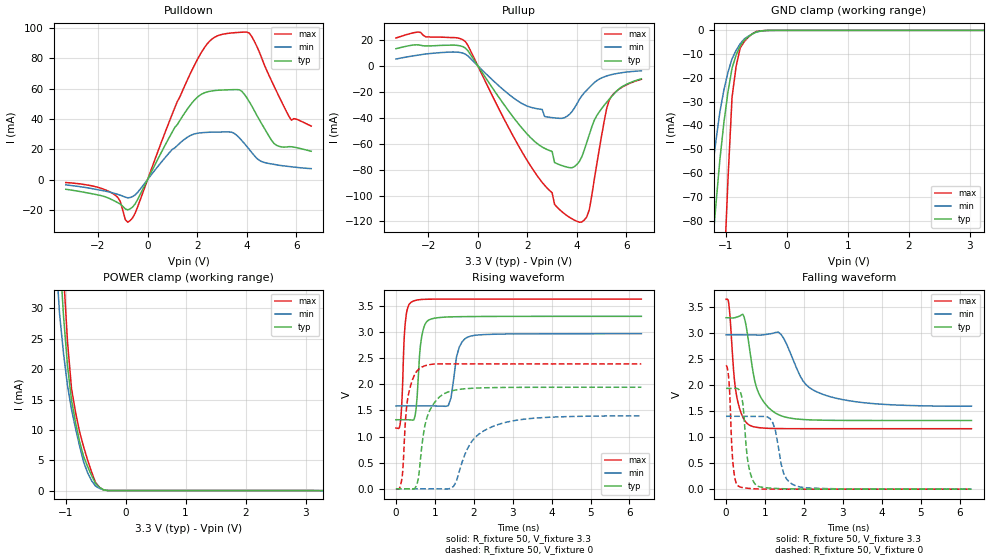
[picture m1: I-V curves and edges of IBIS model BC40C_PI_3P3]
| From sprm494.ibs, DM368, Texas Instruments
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|   Model Cell BC40C_PI_3P3
|BC1833DV40CTHYPBFZP_PI_3P3
[Model]   BC40C_PI_3P3
Model_type   I/O
Polarity   Non-Inverting
Enable   Active-Low
Vinl =  0.8V
Vinh =  2V
Cref =  15pF
Rref =  100.00M
Vref =  0V
Vmeas =  1.65
C_comp   1.827461p   1.619679p   1.938505p
[Model Spec]
Vinl   0.8V   0.8V   0.8V
Vinh   2V   2V   2V
[Temperature Range]   25   125   -40
[Voltage Range]   3.3   2.97   3.63
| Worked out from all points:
|   slope of the pulldown table from 0 to 0.495 V, typ, clamps not added: 30.9 ohm
|   slope of the pullup table from 0 to 0.495 V, typ, clamps not added: 34.5 ohm
|   GND clamp passes 1 mA (typ) near -0.53 V on its own axis
|   POWER clamp passes 1 mA (typ) near -0.48 V on its own axis
|   rising waveform, R_fixture 50, V_fixture 3.3: 20-80 % time 121ps typ, 180ps min, 84.2ps max; typ from 1.32 V to 3.3 V
|   rising waveform, R_fixture 50, V_fixture 0: 20-80 % time 301ps typ, 668ps min, 168ps max; typ from 0 V to 1.94 V
|   falling waveform, R_fixture 50, V_fixture 3.3: 20-80 % time 369ps typ, 724ps min, 192ps max; typ from 3.3 V to 1.32 V
|   falling waveform, R_fixture 50, V_fixture 0: 20-80 % time 154ps typ, 225ps min, 91.4ps max; typ from 1.94 V to 0 V
[POWER_clamp]
|   voltage   I(typ)   I(min)   I(max)
-3.3V     651.1mA    752.4mA    734.3mA
-1.167V   54.2mA     39.67mA    68.27mA
-1.1V     39.46mA    29.18mA    50.26mA
-1.033V   28.73mA    22.56mA    35.65mA
-966.7mV  20.54mA    17.28mA    24.49mA
-900mV    14.89mA    13.34mA    16.79mA
-833.3mV  11.22mA    10.26mA    12.9mA
-700mV    5.654mA    4.759mA    7.265mA
-633.3mV  3.989mA    2.971mA    5.071mA
-500mV    1.175mA    749.7uA    1.318mA
-433.3mV  515.5uA    352.4uA    536.9uA
3.3V      -1.387nA   -62.23uA   -207.7pA
[Pulldown]
|   voltage   I(typ)   I(min)   I(max)
-3.3V     -6.422mA   -3.532mA   -2.011mA
-1.4V     -13.61mA   -8.844mA   -9.294mA
-900mV    -19.41mA   -11.63mA   -26.5mA
-700mV    -19.32mA   -11.87mA   -27.02mA
1.7V      48.59mA    28.8mA     69.05mA
2.4V      57.75mA    31.1mA     89.36mA
3V        58.98mA    31.34mA    95.71mA
3.7V      59.15mA    27.45mA    97.03mA
4.1V      51.29mA    19.83mA    96.56mA
5.1V      23.75mA    9.981mA    61.57mA
5.8V      21.6mA     8.404mA    39.13mA
6.6V      18.63mA    7.176mA    35.23mA
[Pullup]
|   voltage   I(typ)   I(min)   I(max)
-3.3V     13.07mA    5.064mA    21.3mA
-2.4V     16.03mA    8.135mA    25.87mA
-500mV    13.57mA    8.888mA    18.56mA
1.6V      -43.76mA   -26.97mA   -60.15mA
2.6V      -62.65mA   -33.77mA   -89.9mA
2.7V      -63.7mA    -39.17mA   -92.19mA
3.5V      -77.59mA   -40.04mA   -114.1mA
4.1V      -73.82mA   -26mA      -120.5mA
4.5V      -53.1mA    -16.83mA   -111mA
5.1V      -30.55mA   -8.632mA   -42.91mA
5.3V      -25.94mA   -7.357mA   -26.67mA
6.6V      -10.13mA   -3.951mA   -10.53mA
[GND_clamp]
|   voltage   I(typ)   I(min)   I(max)
-3.3V     -797.2mA   -785.7mA   -1.904A
-1.367V   -137mA     -90.17mA   -361mA
-1.3V     -115.1mA   -74.74mA   -306.9mA
-1.233V   -94.06mA   -60.33mA   -253.5mA
-1.167V   -73.82mA   -46.85mA   -201.1mA
-1.033V   -38.67mA   -25.03mA   -103.1mA
-966.7mV  -25.83mA   -17.58mA   -62.61mA
-900mV    -15.9mA    -11.94mA   -28.1mA
-833.3mV  -10.41mA   -8.424mA   -15.19mA
-766.7mV  -6.511mA   -5.657mA   -7.41mA
-500mV    -569.8uA   -729.9uA   -439.2uA
3.233V    1.233uA    14.79uA    3.427uA
[Ramp]
| variable   typ   min   max
dV/dt_f   1.227841/0.3664319n  0.8646145/0.7425802n   1.497221/0.1916096n
dV/dt_r   1.169259/0.3008263n  0.8437538/0.6800557n   1.438756/0.167493n
R_load = 50
[Rising Waveform]
R_fixture = 50
V_fixture = 3.3
V_fixture_min = 2.97
V_fixture_max = 3.63
|   time   V(typ)   V(min)   V(max)
0s        1.321V     1.585V     1.161V
120ps     1.321V     1.585V     1.304V
264ps     1.321V     1.585V     3.323V
432ps     1.312V     1.585V     3.586V
660ps     2.902V     1.585V     3.623V
858ps     3.234V     1.585V     3.627V
1.344ns   3.288V     1.588V     3.629V
1.626ns   3.293V     2.709V     3.63V
1.908ns   3.295V     2.919V     3.63V
6.306ns   3.3V       2.967V     3.63V
[Rising Waveform]
R_fixture = 50
V_fixture = 0
V_fixture_min = 0
V_fixture_max = 0
|   time   V(typ)   V(min)   V(max)
0s        10.46uV    -43.28nV   -1.575mV
162ps     4.722uV    6.129uV    238.9mV
336ps     -1.269mV   7.587uV    1.853V
546ps     101.3mV    6.372uV    2.258V
660ps     781mV      6.13uV     2.327V
888ps     1.526V     21.09uV    2.378V
1.416ns   1.87V      9.56mV     2.39V
1.908ns   1.921V     860.7mV    2.389V
2.544ns   1.936V     1.209V     2.389V
6.306ns   1.943V     1.394V     2.388V
[Falling Waveform]
R_fixture = 50
V_fixture = 3.3
V_fixture_min = 2.97
V_fixture_max = 3.63
|   time   V(typ)   V(min)   V(max)
0s        3.299V     2.97V      3.653V
72ps      3.297V     2.97V      3.561V
276ps     3.311V     2.97V      1.776V
462ps     3.318V     2.97V      1.341V
606ps     2.691V     2.969V     1.231V
858ps     1.817V     2.965V     1.183V
1.482ns   1.396V     2.902V     1.165V
1.98ns    1.34V      2.08V      1.163V
2.496ns   1.327V     1.822V     1.163V
6.306ns   1.321V     1.597V     1.163V
[Falling Waveform]
R_fixture = 50
V_fixture = 0
V_fixture_min = 0
V_fixture_max = 0
|   time   V(typ)   V(min)   V(max)
0s        1.941V     1.402V     2.384V
72ps      1.94V      1.402V     2.104V
192ps     1.939V     1.402V     396.3mV
336ps     1.912V     1.402V     51.01mV
576ps     463.5mV    1.401V     15.62mV
834ps     52.34mV    1.4V       3.85mV
1.2ns     17.1mV     1.28V      394.1uV
1.482ns   8.125mV    299.7mV    -9.22uV
1.836ns   3.859mV    53.76mV    -57.91uV
6.306ns   61.8uV     1.65mV     309.6nV
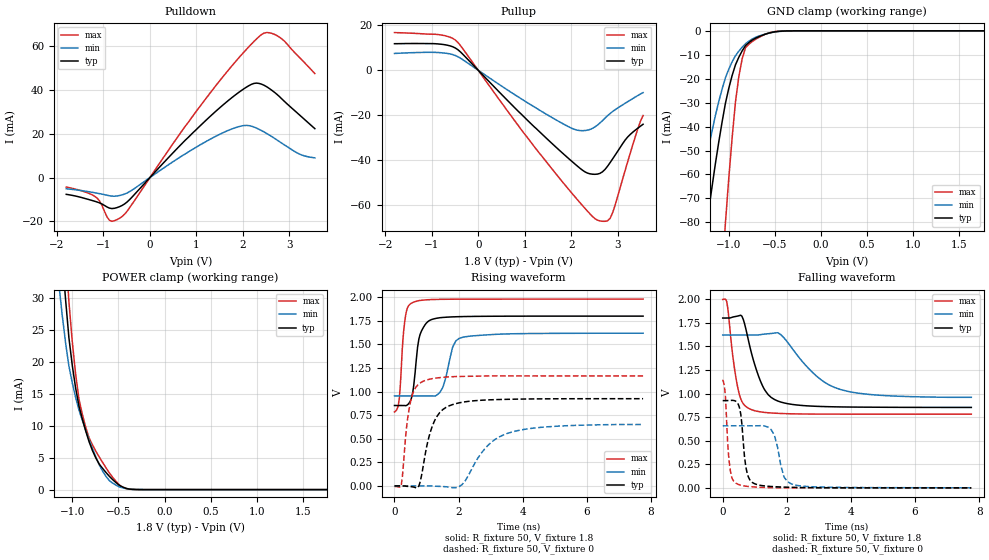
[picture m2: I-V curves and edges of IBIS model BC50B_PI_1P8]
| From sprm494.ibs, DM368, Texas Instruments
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|   Model Cell BC50B_PI_1P8
|BC1833DV50BTHYPBFZP_PI_1P8
[Model]   BC50B_PI_1P8
Model_type   I/O
Polarity   Non-Inverting
Enable   Active-Low
Vinl =  0.63V
Vinh =  1.17V
Cref =  15pF
Rref =  100.00M
Vref =  0V
Vmeas =  0.9
C_comp   1.889253p   1.773057p   1.933707p
[Model Spec]
Vinl   0.63V   0.567V   0.693V
Vinh   1.17V   1.053V   1.287V
[Temperature Range]   25   125   -40
[Voltage Range]   1.8   1.62   1.98
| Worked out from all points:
|   slope of the pulldown table from 0 to 0.27 V, typ, clamps not added: 43.6 ohm
|   slope of the pullup table from 0 to 0.27 V, typ, clamps not added: 46.6 ohm
|   GND clamp passes 1 mA (typ) near -0.57 V on its own axis
|   POWER clamp passes 1 mA (typ) near -0.52 V on its own axis
|   rising waveform, R_fixture 50, V_fixture 1.8: 20-80 % time 214ps typ, 291ps min, 146ps max; typ from 0.852 V to 1.8 V
|   rising waveform, R_fixture 50, V_fixture 0: 20-80 % time 448ps typ, 942ps min, 249ps max; typ from 0 V to 0.925 V
|   falling waveform, R_fixture 50, V_fixture 1.8: 20-80 % time 533ps typ, 1.17ns min, 289ps max; typ from 1.8 V to 0.853 V
|   falling waveform, R_fixture 50, V_fixture 0: 20-80 % time 167ps typ, 260ps min, 128ps max; typ from 0.925 V to 0 V
[POWER_clamp]
|   voltage   I(typ)   I(min)   I(max)
-1.8V     212.4mA    175.3mA    247mA
-1.145V   43.7mA     32.21mA    55.25mA
-1.109V   36.42mA    27.3mA     46.11mA
-1.073V   29.77mA    23mA       37.5mA
-1.036V   23.75mA    19.32mA    29.4mA
-963.6mV  15.88mA    14.42mA    18.07mA
-927.3mV  13.07mA    12.46mA    14.17mA
-854.5mV  9.189mA    9.275mA    9.761mA
-672.7mV  3.345mA    2.932mA    4.282mA
-527.3mV  1.106mA    699.3uA    1.308mA
-345.5mV  37.84uA    37.74uA    25.03uA
1.764V    -598pA     -801.6nA   -245.7pA
[Pulldown]
|   voltage   I(typ)   I(min)   I(max)
-1.8V     -7.67mA    -5.126mA   -4.339mA
-1.145V   -11.1mA    -7.106mA   -9.219mA
-872.7mV  -13.94mA   -8.311mA   -19.49mA
-600mV    -12.75mA   -7.913mA   -17.78mA
763.6mV   17.11mA    10.84mA    23.53mA
1.636V    34.26mA    21.05mA    47.69mA
2.182V    42.48mA    23.41mA    60.84mA
2.455V    42.04mA    20.75mA    65.84mA
2.618V    39.8mA     18.68mA    65.73mA
2.836V    35.82mA    15.63mA    63.15mA
3.218V    28.47mA    10.66mA    54.66mA
3.545V    22.28mA    8.953mA    47.39mA
[Pullup]
|   voltage   I(typ)   I(min)   I(max)
-1.8V     11.79mA    7.463mA    16.74mA
-872.7mV  11.71mA    7.882mA    15.87mA
-490.9mV  9.875mA    6.533mA    13.41mA
981.8mV   -20.64mA   -13.44mA   -27.9mA
1.964V    -39.57mA   -25.31mA   -53.37mA
2.291V    -45.08mA   -26.79mA   -61.23mA
2.564V    -46.14mA   -24.37mA   -66.57mA
2.782V    -42.64mA   -20.2mA    -66.89mA
2.891V    -39.36mA   -18.32mA   -63.26mA
3.218V    -29.56mA   -13.93mA   -40.37mA
3.436V    -25.67mA   -11.18mA   -25.75mA
3.545V    -23.99mA   -9.92mA    -20.12mA
[GND_clamp]
|   voltage   I(typ)   I(min)   I(max)
-1.8V     -250.5mA   -178.5mA   -583.4mA
-1.364V   -117.1mA   -78.71mA   -289.4mA
-1.255V   -85.44mA   -55.93mA   -216.8mA
-1.218V   -75.29mA   -48.85mA   -193mA
-1.036V   -30.33mA   -19.65mA   -80.48mA
-963.6mV  -18.7mA    -12.96mA   -44.84mA
-927.3mV  -14.22mA   -10.39mA   -29.72mA
-890.9mV  -11.04mA   -8.503mA   -19.19mA
-818.2mV  -6.173mA   -5.398mA   -7.049mA
-745.5mV  -3.853mA   -3.43mA    -4.455mA
-418.2mV  -112.1uA   -167uA     -90.75uA
1.764V    13.63nA    373.3nA    10.44nA
[Ramp]
| variable   typ   min   max
dV/dt_f  0.5864323/0.5382612n  0.4143331/1.208065n   0.731688/0.2890759n
dV/dt_r  0.5679605/0.4461851n  0.4061971/0.9694832n  0.7075469/0.2490038n
R_load = 50
[Rising Waveform]
R_fixture = 50
V_fixture = 1.8
V_fixture_min = 1.62
V_fixture_max = 1.98
|   time   V(typ)   V(min)   V(max)
0s        852.4mV    954.1mV    784mV
150ps     852.4mV    954.1mV    928.2mV
348ps     850.4mV    954.1mV    1.809V
564ps     979.7mV    954.1mV    1.943V
762ps     1.558V     954.1mV    1.964V
1.158ns   1.764V     953.8mV    1.975V
1.512ns   1.786V     1.047V     1.978V
1.812ns   1.792V     1.468V     1.979V
2.112ns   1.795V     1.574V     1.98V
7.758ns   1.8V       1.619V     1.98V
[Rising Waveform]
R_fixture = 50
V_fixture = 0
V_fixture_min = 0
V_fixture_max = 0
|   time   V(typ)   V(min)   V(max)
0s        10.69uV    14.59uV    -4.323mV
216ps     61.39uV    17.47uV    18.44mV
390ps     -4.252mV   14.6uV     660.9mV
522ps     -8.208mV   9.129uV    923.7mV
762ps     580.2uV    2.608uV    1.08V
918ps     254.8mV    13.3uV     1.113V
1.314ns   731.4mV    -3.961mV   1.144V
1.914ns   872.2mV    -18.33mV   1.159V
3.498ns   917.7mV    553.8mV    1.166V
7.758ns   924.5mV    651mV      1.166V
[Falling Waveform]
R_fixture = 50
V_fixture = 1.8
V_fixture_min = 1.62
V_fixture_max = 1.98
|   time   V(typ)   V(min)   V(max)
0s        1.8V       1.62V      1.997V
126ps     1.8V       1.62V      1.971V
498ps     1.824V     1.62V      1.019V
642ps     1.785V     1.62V      891.3mV
840ps     1.507V     1.62V      837.6mV
1.272ns   1.062V     1.629V     801.1mV
1.812ns   909.6mV    1.625V     788.5mV
2.91ns    864.5mV    1.19V      782mV
3.684ns   857.9mV    1.041V     781.5mV
7.758ns   852.6mV    959.9mV    781.3mV
[Falling Waveform]
R_fixture = 50
V_fixture = 0
V_fixture_min = 0
V_fixture_max = 0
|   time   V(typ)   V(min)   V(max)
0s        924.7mV    657.4mV    1.146V
66ps      924.5mV    657.4mV    1.037V
240ps     925.2mV    657.4mV    179.5mV
480ps     888.5mV    657.5mV    37.94mV
762ps     156.3mV    657.4mV    16.13mV
1.038ns   38.34mV    657.9mV    8.334mV
1.512ns   14.43mV    617.1mV    2.247mV
1.914ns   8.112mV    113.9mV    728.2uV
2.214ns   5.25mV     33.91mV    318.6uV
7.758ns   35.96uV    1.079mV    4.576uV
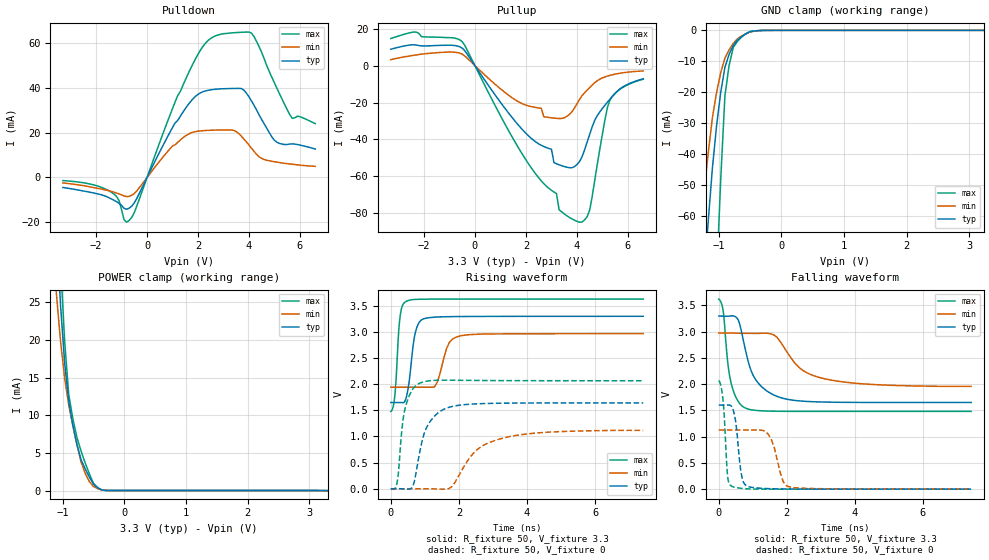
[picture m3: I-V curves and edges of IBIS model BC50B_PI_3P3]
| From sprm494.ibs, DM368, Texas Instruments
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|   Model Cell BC50B_PI_3P3
|BC1833DV50BTHYPBFZP_PI_3P3
[Model]   BC50B_PI_3P3
Model_type   I/O
Polarity   Non-Inverting
Enable   Active-Low
Vinl =  0.8V
Vinh =  2V
Cref =  15pF
Rref =  100.00M
Vref =  0V
Vmeas =  1.65
C_comp   1.614302p   1.431606p   1.718607p
[Model Spec]
Vinl   0.8V   0.8V   0.8V
Vinh   2V   2V   2V
[Temperature Range]   25   125   -40
[Voltage Range]   3.3   2.97   3.63
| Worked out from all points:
|   slope of the pulldown table from 0 to 0.495 V, typ, clamps not added: 43.6 ohm
|   slope of the pullup table from 0 to 0.495 V, typ, clamps not added: 49.2 ohm
|   GND clamp passes 1 mA (typ) near -0.55 V on its own axis
|   POWER clamp passes 1 mA (typ) near -0.51 V on its own axis
|   rising waveform, R_fixture 50, V_fixture 3.3: 20-80 % time 192ps typ, 275ps min, 121ps max; typ from 1.65 V to 3.3 V
|   rising waveform, R_fixture 50, V_fixture 0: 20-80 % time 439ps typ, 954ps min, 234ps max; typ from 0 V to 1.64 V
|   falling waveform, R_fixture 50, V_fixture 3.3: 20-80 % time 538ps typ, 948ps min, 248ps max; typ from 3.29 V to 1.65 V
|   falling waveform, R_fixture 50, V_fixture 0: 20-80 % time 156ps typ, 282ps min, 108ps max; typ from 1.6 V to 0 V
[POWER_clamp]
|   voltage   I(typ)   I(min)   I(max)
-3.3V     629.5mA    736.9mA    707.5mA
-1.1V     34.8mA     26.08mA    44.2mA
-1.033V   24.58mA    19.82mA    30.25mA
-966.7mV  16.91mA    14.91mA    19.76mA
-900mV    11.78mA    11.33mA    12.72mA
-833.3mV  8.631mA    8.595mA    9.514mA
-700mV    4.074mA    3.769mA    5.222mA
-633.3mV  2.869mA    2.274mA    3.645mA
-500mV    840.7uA    536.5uA    943.2uA
-433.3mV  368.4uA    251.7uA    384.4uA
-300mV    10.23uA    13.48uA    7.707uA
3.3V      -1.092nA   -54.94uA   -162.3pA
[Pulldown]
|   voltage   I(typ)   I(min)   I(max)
-3.3V     -4.448mA   -2.4mA     -1.374mA
-1.4V     -9.542mA   -6.187mA   -6.549mA
-900mV    -13.71mA   -8.202mA   -18.8mA
-700mV    -13.65mA   -8.389mA   -19.1mA
1.7V      33.68mA    19.73mA    48.3mA
2.3V      38.57mA    20.92mA    59.89mA
2.9V      39.49mA    21.13mA    63.8mA
3.7V      39.58mA    18.37mA    64.65mA
4.1V      34.01mA    13mA       64.27mA
5V        16.52mA    7.025mA    42.04mA
5.7V      14.97mA    5.897mA    26.31mA
6.6V      12.66mA    4.964mA    23.97mA
[Pullup]
|   voltage   I(typ)   I(min)   I(max)
-3.3V     8.925mA    3.225mA    14.72mA
-500mV    9.531mA    6.242mA    13.04mA
1.6V      -30.57mA   -18.73mA   -42.11mA
2.7V      -43.89mA   -27.7mA    -64.03mA
3V        -45.38mA   -28.31mA   -67.67mA
3.2V      -53.28mA   -28.6mA    -69.43mA
3.3V      -53.83mA   -28.7mA    -78.25mA
4.1V      -52.1mA    -18.35mA   -84.99mA
4.5V      -37.33mA   -11.85mA   -78.48mA
5.1V      -21.45mA   -6.119mA   -29.35mA
5.3V      -18.16mA   -5.226mA   -18.53mA
6.6V      -7.127mA   -2.839mA   -7.361mA
[GND_clamp]
|   voltage   I(typ)   I(min)   I(max)
-3.3V     -715.9mA   -742.1mA   -1.572A
-1.3V     -98.62mA   -65.27mA   -247mA
-1.233V   -79.79mA   -52mA      -203.1mA
-1.167V   -61.75mA   -39.66mA   -160.1mA
-1.1V     -44.51mA   -28.24mA   -117.9mA
-1.033V   -30.84mA   -20.05mA   -80.27mA
-966.7mV  -19.98mA   -13.63mA   -48.02mA
-900mV    -11.93mA   -9mA       -21.14mA
-833.3mV  -7.773mA   -6.305mA   -11.37mA
-766.7mV  -4.835mA   -4.205mA   -5.503mA
-500mV    -452.3uA   -556.4uA   -368.2uA
3.233V    1.233uA    10.64uA    3.427uA
[Ramp]
| variable   typ   min   max
dV/dt_f   0.990177/0.5359479n  0.6157662/0.9866483n   1.289918/0.2477444n
dV/dt_r  0.9905826/0.4381166n  0.6807741/0.9841005n   1.251316/0.2373601n
R_load = 50
[Rising Waveform]
R_fixture = 50
V_fixture = 3.3
V_fixture_min = 2.97
V_fixture_max = 3.63
|   time   V(typ)   V(min)   V(max)
0s        1.65V      1.944V     1.479V
120ps     1.65V      1.944V     1.797V
276ps     1.65V      1.944V     3.311V
468ps     1.78V      1.944V     3.591V
726ps     3.003V     1.944V     3.624V
978ps     3.254V     1.944V     3.628V
1.284ns   3.284V     1.948V     3.629V
1.716ns   3.293V     2.797V     3.629V
2.064ns   3.296V     2.928V     3.63V
7.416ns   3.3V       2.968V     3.63V
[Rising Waveform]
R_fixture = 50
V_fixture = 0
V_fixture_min = 0
V_fixture_max = 0
|   time   V(typ)   V(min)   V(max)
0s        4.1uV      9.798uV    -3.527mV
198ps     6.665uV    12.37uV    167.9mV
330ps     -500.4uV   11.44uV    1.162V
450ps     -7.136mV   6.659uV    1.61V
648ps     50.44mV    1.262uV    1.911V
870ps     766.3mV    795.5nV    2.025V
1.164ns   1.295V     -302.5uV   2.067V
1.806ns   1.575V     47.84mV    2.077V
3.114ns   1.636V     936.1mV    2.07V
7.416ns   1.643V     1.117V     2.067V
[Falling Waveform]
R_fixture = 50
V_fixture = 3.3
V_fixture_min = 2.97
V_fixture_max = 3.63
|   time   V(typ)   V(min)   V(max)
0s        3.295V     2.97V      3.618V
120ps     3.292V     2.97V      3.435V
276ps     3.291V     2.97V      2.35V
372ps     3.298V     2.97V      1.998V
576ps     3.216V     2.968V     1.666V
798ps     2.612V     2.965V     1.54V
1.164ns   2.017V     2.964V     1.495V
1.98ns    1.715V     2.635V     1.481V
3.3ns     1.655V     2.076V     1.48V
7.416ns   1.65V      1.956V     1.48V
[Falling Waveform]
R_fixture = 50
V_fixture = 0
V_fixture_min = 0
V_fixture_max = 0
|   time   V(typ)   V(min)   V(max)
0s        1.602V     1.127V     2.068V
138ps     1.6V       1.127V     1.62V
276ps     1.6V       1.127V     172mV
408ps     1.536V     1.127V     47.25mV
690ps     203.7mV    1.125V     14.21mV
870ps     48.73mV    1.125V     5.582mV
1.458ns   10.25mV    1.043V     329.3uV
1.89ns    4.314mV    148mV      49.94uV
2.064ns   3.244mV    45.63mV    25.98uV
7.416ns   26.85uV    1.226mV    300.2nV
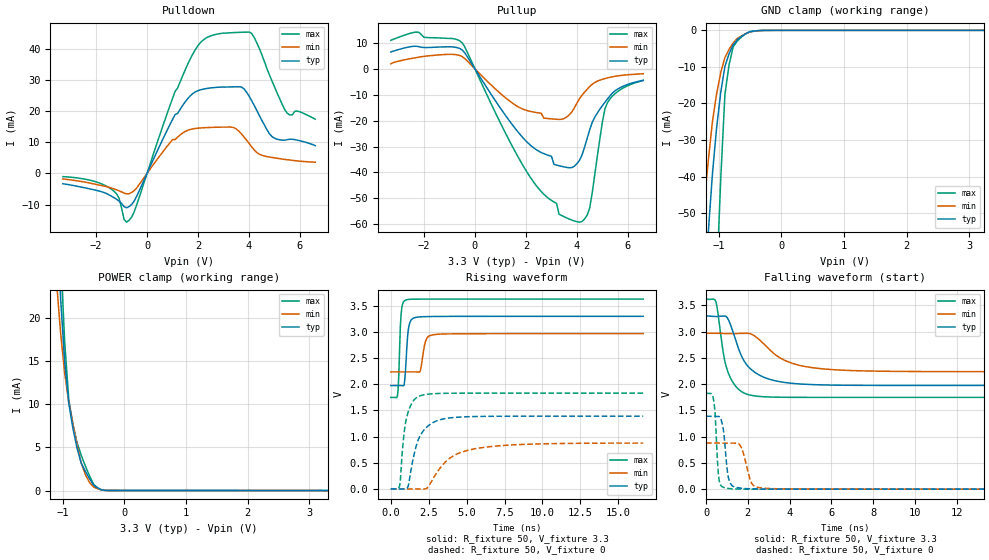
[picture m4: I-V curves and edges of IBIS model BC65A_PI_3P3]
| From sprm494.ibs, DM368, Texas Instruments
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|   Model Cell BC65A_PI_3P3
|BC1833DV65ATHYPBFZP_PI_3P3
[Model]   BC65A_PI_3P3
Model_type   I/O
Polarity   Non-Inverting
Enable   Active-Low
Vinl =  0.8V
Vinh =  2V
Cref =  15pF
Rref =  100.00M
Vref =  0V
Vmeas =  1.65
C_comp   1.512681p   1.336608p   1.607201p
[Model Spec]
Vinl   0.8V   0.8V   0.8V
Vinh   2V   2V   2V
[Temperature Range]   25   125   -40
[Voltage Range]   3.3   2.97   3.63
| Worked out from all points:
|   slope of the pulldown table from 0 to 0.495 V, typ, clamps not added: 56.1 ohm
|   slope of the pullup table from 0 to 0.495 V, typ, clamps not added: 64.3 ohm
|   GND clamp passes 1 mA (typ) near -0.57 V on its own axis
|   POWER clamp passes 1 mA (typ) near -0.53 V on its own axis
|   rising waveform, R_fixture 50, V_fixture 3.3: 20-80 % time 187ps typ, 265ps min, 142ps max; typ from 1.98 V to 3.3 V
|   rising waveform, R_fixture 50, V_fixture 0: 20-80 % time 868ps typ, 1.9ns min, 464ps max; typ from 0 V to 1.39 V
|   falling waveform, R_fixture 50, V_fixture 3.3: 20-80 % time 1.03ns typ, 1.62ns min, 561ps max; typ from 3.3 V to 1.98 V
|   falling waveform, R_fixture 50, V_fixture 0: 20-80 % time 211ps typ, 345ps min, 144ps max; typ from 1.39 V to 0 V
[POWER_clamp]
|   voltage   I(typ)   I(min)   I(max)
-3.3V     617.8mA    728.2mA    693.2mA
-1.1V     32.24mA    24.35mA    40.94mA
-1.033V   22.3mA     18.29mA    27.34mA
-966.7mV  14.91mA    13.58mA    17.2mA
-900mV    10.07mA    10.2mA     10.53mA
-833.3mV  7.206mA    7.664mA    7.683mA
-766.7mV  4.916mA    5.335mA    5.546mA
-700mV    3.204mA    3.214mA    4.114mA
-566.7mV  1.402mA    951.5uA    1.745mA
-500mV    655.5uA    417.3uA    737.8uA
-300mV    8.194uA    10.53uA    6.745uA
3.3V      -930.2pA   -50.66uA   -137.1pA
[Pulldown]
|   voltage   I(typ)   I(min)   I(max)
-3.3V     -3.312mA   -1.764mA   -1.021mA
-1.4V     -7.283mA   -4.687mA   -5.038mA
-1.1V     -8.83mA    -5.573mA   -7.893mA
-900mV    -10.65mA   -6.307mA   -14.74mA
-700mV    -10.64mA   -6.484mA   -15mA
1.6V      24.01mA    13.84mA    35.08mA
2.7V      27.57mA    14.8mA     44.57mA
3.7V      27.7mA     12.68mA    45.26mA
4.1V      23.38mA    8.578mA    44.92mA
4.9V      11.81mA    5.118mA    29.68mA
5.5V      10.83mA    4.397mA    19.31mA
6.6V      8.906mA    3.589mA    17.38mA
[Pullup]
|   voltage   I(typ)   I(min)   I(max)
-3.3V     6.54mA     1.969mA    11.03mA
-2.3V     8.757mA    4.357mA    14.22mA
-500mV    7.317mA    4.758mA    10.08mA
1.6V      -23.29mA   -14.09mA   -32.38mA
2.7V      -32.76mA   -19.04mA   -48.43mA
3.2V      -37.19mA   -19.48mA   -51.99mA
3.5V      -37.9mA    -19.18mA   -57.17mA
4.1V      -35.37mA   -11.52mA   -59.26mA
4.5V      -23.57mA   -6.848mA   -53.81mA
5V        -14.2mA    -4.028mA   -20.44mA
5.2V      -11.59mA   -3.459mA   -13.01mA
6.6V      -4.403mA   -1.883mA   -4.482mA
[GND_clamp]
|   voltage   I(typ)   I(min)   I(max)
-3.3V     -675.4mA   -720mA     -1.407A
-1.3V     -90.36mA   -60.4mA    -217.3mA
-1.233V   -72.63mA   -47.73mA   -178.1mA
-1.167V   -55.68mA   -35.96mA   -139.7mA
-1.1V     -39.52mA   -25.1mA    -102.1mA
-1.033V   -26.87mA   -17.46mA   -68.92mA
-966.7mV  -16.99mA   -11.58mA   -40.74mA
-900mV    -9.874mA   -7.451mA   -17.62mA
-833.3mV  -6.381mA   -5.175mA   -9.397mA
-766.7mV  -3.931mA   -3.418mA   -4.484mA
-500mV    -384.6uA   -457.3uA   -326.8uA
3.233V    1.233uA    8.331uA    3.427uA
[Ramp]
| variable   typ   min   max
dV/dt_f  0.7941926/1.027615n   0.4393814/1.617365n   1.128694/0.5611214n
dV/dt_r  0.8373573/0.8674574n  0.5298839/1.923192n   1.101496/0.4632458n
R_load = 50
[Rising Waveform]
R_fixture = 50
V_fixture = 3.3
V_fixture_min = 2.97
V_fixture_max = 3.63
|   time   V(typ)   V(min)   V(max)
0s        1.976V     2.238V     1.749V
432ps     1.976V     2.238V     1.762V
676ps     1.976V     2.238V     3.331V
868ps     1.978V     2.238V     3.588V
1.012ns   2.477V     2.238V     3.615V
1.212ns   3.136V     2.238V     3.624V
1.712ns   3.283V     2.237V     3.628V
2.392ns   3.294V     2.892V     3.629V
2.864ns   3.297V     2.95V      3.63V
16.64ns   3.3V       2.97V      3.63V
[Rising Waveform]
R_fixture = 50
V_fixture = 0
V_fixture_min = 0
V_fixture_max = 0
|   time   V(typ)   V(min)   V(max)
0s        8.913uV    -803.7nV   16.95uV
580ps     1.168uV    8.285uV    58.61mV
868ps     -3.817mV   6.621uV    1.048V
1.108ns   25.58mV    5.352uV    1.435V
1.604ns   743.9mV    -114.7uV   1.723V
1.936ns   1.017V     -3.235mV   1.78V
2.392ns   1.188V     15.3mV     1.809V
2.984ns   1.296V     289.5mV    1.823V
5.148ns   1.381V     743.6mV    1.831V
16.64ns   1.391V     875.8mV    1.831V
[Falling Waveform]
R_fixture = 50
V_fixture = 3.3
V_fixture_min = 2.97
V_fixture_max = 3.63
|   time   V(typ)   V(min)   V(max)
0s        3.3V       2.97V      3.622V
480ps     3.29V      2.97V      3.556V
868ps     3.299V     2.966V     2.496V
1.108ns   3.192V     2.964V     2.171V
1.66ns    2.569V     2.968V     1.869V
2.048ns   2.323V     2.968V     1.799V
2.748ns   2.135V     2.773V     1.761V
3.696ns   2.037V     2.468V     1.751V
5.148ns   1.992V     2.311V     1.749V
16.64ns   1.976V     2.238V     1.749V
[Falling Waveform]
R_fixture = 50
V_fixture = 0
V_fixture_min = 0
V_fixture_max = 0
|   time   V(typ)   V(min)   V(max)
0s        1.391V     878.8mV    1.826V
336ps     1.387V     878.8mV    1.747V
432ps     1.387V     878.8mV    1.446V
628ps     1.381V     878.2mV    157.9mV
916ps     774.6mV    876.9mV    25.29mV
1.212ns   80.99mV    877.1mV    6.901mV
1.604ns   22.94mV    849.1mV    1.505mV
2.16ns    6.208mV    129.4mV    268.7uV
2.628ns   2.919mV    24.39mV    82.17uV
16.64ns   205.3nV    160.5uV    142.7nV
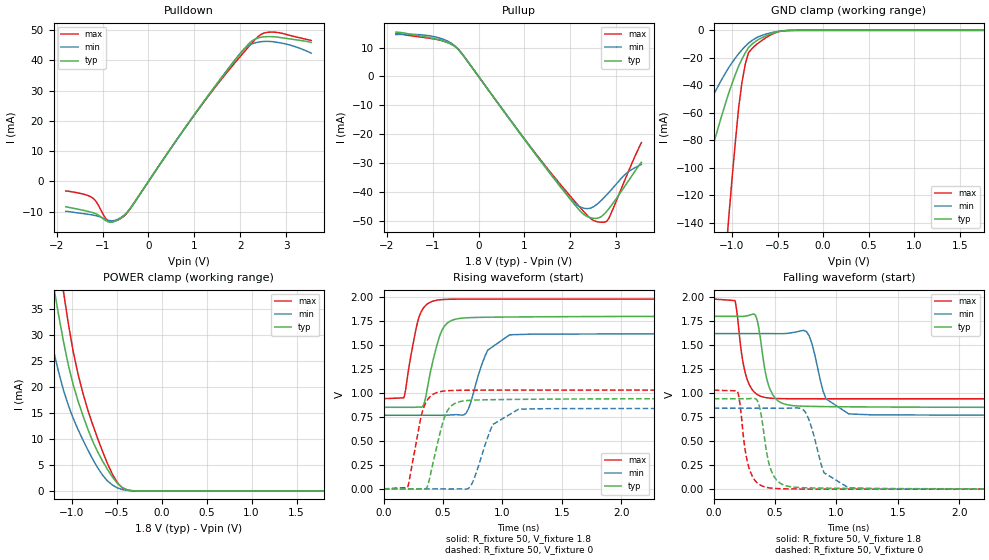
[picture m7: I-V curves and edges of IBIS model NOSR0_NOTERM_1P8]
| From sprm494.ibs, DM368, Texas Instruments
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|   Model Cell NOSR0_NOTERM_1P8
|NOSR0_NOTERM_1P8
[Model]   NOSR0_NOTERM_1P8
Model_type   I/O
Polarity   Non-Inverting
Enable   Active-Low
Vinl = 0.8V
Vinh = 2V
Cref =  15.0000pF
Rref =  100.0000M
Vref =  0V
Vmeas =  0.9
C_comp   3.009089p   2.23501p   3.950269p
[Model Spec]
Vinl   0.8V   0.8V   0.8V
Vinh   2V   2V   2V
[Temperature Range]   25   125   -40
[Voltage Range]   1.8   1.62   1.98
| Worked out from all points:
|   slope of the pulldown table from 0 to 0.27 V, typ, clamps not added: 44.1 ohm
|   slope of the pullup table from 0 to 0.27 V, typ, clamps not added: 45.3 ohm
|   GND clamp passes 1 mA (typ) near -0.50 V on its own axis
|   POWER clamp passes 1 mA (typ) near -0.46 V on its own axis
|   rising waveform, R_fixture 50, V_fixture 1.8: 20-80 % time 110ps typ, 136ps min, 94.7ps max; typ from 0.851 V to 1.8 V
|   rising waveform, R_fixture 50, V_fixture 0: 20-80 % time 113ps typ, 142ps min, 98.3ps max; typ from 0 V to 0.942 V
|   falling waveform, R_fixture 50, V_fixture 1.8: 20-80 % time 83.4ps typ, 103ps min, 75.9ps max; typ from 1.8 V to 0.851 V
|   falling waveform, R_fixture 50, V_fixture 0: 20-80 % time 81ps typ, 111ps min, 72.1ps max; typ from 0.942 V to 0 V
[POWER_clamp]
|   voltage   I(typ)   I(min)   I(max)
-1.8V     107.1mA    82.38mA    134mA
-1.327V   53.28mA    37.63mA    69.44mA
-1.182V   37.78mA    25.73mA    50.07mA
-1.091V   28.94mA    19.52mA    38.61mA
-1.073V   27.41mA    18.52mA    36.52mA
-981.8mV  20.5mA     14.01mA    26.9mA
-872.7mV  14.5mA     9.789mA    18.8mA
-709.1mV  7.513mA    4.451mA    10.09mA
-545.5mV  2.674mA    1.139mA    3.21mA
-436.4mV  654.9uA    255.5uA    594.4uA
-327.3mV  54.9uA     31.45uA    28.93uA
1.8V      5.504nA    118.5nA    1.898nA
[Pulldown]
|   voltage   I(typ)   I(min)   I(max)
-1.8V     -8.351mA   -9.832mA   -3.116mA
-1.2V     -10.35mA   -11.12mA   -5.615mA
-872.7mV  -13.35mA   -12.83mA   -13.13mA
-600mV    -12.16mA   -11.91mA   -12.18mA
-381.8mV  -8.669mA   -8.547mA   -8.669mA
1.145V    25.19mA    25.08mA    24.97mA
1.855V    39.42mA    39.58mA    38.69mA
2.127V    44.53mA    44.34mA    43.55mA
2.291V    46.79mA    45.65mA    46.35mA
2.564V    47.83mA    46.29mA    49.2mA
3.055V    47.15mA    45.17mA    48.35mA
3.545V    45.94mA    42.37mA    46.6mA
[Pullup]
|   voltage   I(typ)   I(min)   I(max)
-1.8V     15.34mA    14.46mA    14.83mA
-981.8mV  13.15mA    13.81mA    12.99mA
-709.1mV  11.92mA    12.48mA    11.95mA
-490.9mV  10.05mA    10.19mA    10.14mA
1.145V    -24.96mA   -24.69mA   -24.66mA
2.018V    -42.87mA   -42.71mA   -41.79mA
2.291V    -47.72mA   -45.58mA   -46.74mA
2.509V    -49.09mA   -45.01mA   -49.87mA
2.673V    -48.48mA   -42.88mA   -50.42mA
2.836V    -45.77mA   -40.16mA   -49.13mA
3.218V    -37.2mA    -33.54mA   -34.59mA
3.545V    -29.71mA   -30.45mA   -22.9mA
[GND_clamp]
|   voltage   I(typ)   I(min)   I(max)
-1.8V     -229.3mA   -132mA     -818.5mA
-1.436V   -139.1mA   -79.12mA   -490.7mA
-1.073V   -53.39mA   -31.17mA   -167.2mA
-1.036V   -45.75mA   -27.16mA   -136.8mA
-927.3mV  -26.08mA   -17mA      -56.49mA
-890.9mV  -20.9mA    -14.21mA   -38.02mA
-854.5mV  -16.38mA   -11.64mA   -24.6mA
-818.2mV  -12.5mA    -9.274mA   -16.24mA
-709.1mV  -6.663mA   -4.641mA   -9.158mA
-527.3mV  -1.534mA   -1.158mA   -1.867mA
-381.8mV  -101.4uA   -119.6uA   -85.85uA
1.764V    4.755nA    714.3nA    1.257nA
[Ramp]
| variable   typ   min   max
dV/dt_f  0.5840345/83.79068p   0.5315097/0.104203n   0.6348468/76.13274p
dV/dt_r  0.5671716/0.1130405n  0.5072191/0.1407456n  0.6204798/98.46184p
R_load = 50
[Rising Waveform]
R_fixture = 50
V_fixture = 1.8
V_fixture_min = 1.62
V_fixture_max = 1.98
|   time   V(typ)   V(min)   V(max)
0s        851mV      767.9mV    940.9mV
168.8ps   851mV      767.9mV    949.4mV
276.8ps   852.3mV    767.9mV    1.692V
328.8ps   859.1mV    767.9mV    1.875V
456.8ps   1.534V     767.7mV    1.969V
535.2ps   1.729V     769.2mV    1.977V
696ps     1.784V     791.8mV    1.98V
876ps     1.79V      1.446V     1.98V
1.061ns   1.793V     1.607V     1.98V
5.314ns   1.8V       1.618V     1.98V
[Rising Waveform]
R_fixture = 50
V_fixture = 0
V_fixture_min = 0
V_fixture_max = 0
|   time   V(typ)   V(min)   V(max)
0s        84.48nV    277.2nV    37.22nV
201.6ps   2.862uV    299.7nV    13.85mV
313.6ps   -777.2uV   -567.6nV   743.9mV
356.8ps   1.747mV    575.1nV    903.1mV
504ps     716.4mV    -481uV     1.02V
573.6ps   869.8mV    -1.013mV   1.026V
716ps     922.8mV    6.213mV    1.029V
919.2ps   930.5mV    671.2mV    1.03V
1.137ns   933.6mV    831.7mV    1.03V
6.148ns   942mV      841.2mV    1.031V
[Falling Waveform]
R_fixture = 50
V_fixture = 1.8
V_fixture_min = 1.62
V_fixture_max = 1.98
|   time   V(typ)   V(min)   V(max)
0s        1.8V       1.62V      1.98V
172.8ps   1.8V       1.62V      1.964V
245.6ps   1.8V       1.62V      1.272V
335.2ps   1.819V     1.62V      1.005V
428.8ps   1.165V     1.62V      952.8mV
525.6ps   918.3mV    1.619V     943.5mV
754.4ps   863.1mV    1.643V     941.5mV
914.4ps   859.9mV    940.8mV    941.4mV
1.099ns   857.7mV    784.1mV    941.3mV
5.344ns   851mV      769.5mV    940.9mV
[Falling Waveform]
R_fixture = 50
V_fixture = 0
V_fixture_min = 0
V_fixture_max = 0
|   time   V(typ)   V(min)   V(max)
0s        942mV      842.8mV    1.031V
193.6ps   942mV      842.8mV    1.014V
269.6ps   941.7mV    842.8mV    311.5mV
352.8ps   927.8mV    842.8mV    67.53mV
459.2ps   224.8mV    842.8mV    12.44mV
554.4ps   52.13mV    842.6mV    4.282mV
726.4ps   15.26mV    829.7mV    1.597mV
898.4ps   10.71mV    170.9mV    788.1uV
1.1ns     7.911mV    13.12mV    343.5uV
5.73ns    76.7uV     1.621mV    31.81nV
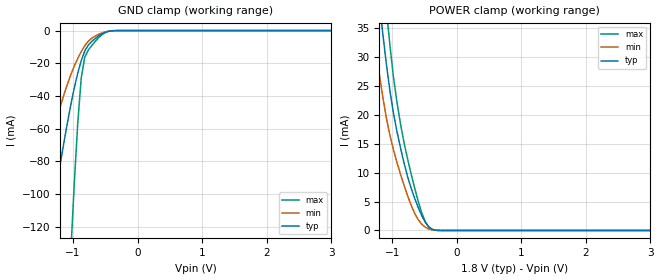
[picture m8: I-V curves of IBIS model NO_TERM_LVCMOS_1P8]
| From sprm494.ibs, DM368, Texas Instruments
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|   Model Cell NO_TERM_LVCMOS_1P8
|NO_TERM_LVCMOS_1P8
[Model]   NO_TERM_LVCMOS_1P8
Model_type   Input
Polarity   Non-Inverting
Vinl =  0.63
Vinh =  1.17
C_comp   3.009089p   2.23501p   3.950269p
[Model Spec]
Vinl   0.63   0.567   0.693
Vinh   1.17   1.053   1.287
[Temperature Range]   25   125   -40
[Voltage Range]   1.8   1.62   1.98
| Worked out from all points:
|   GND clamp passes 1 mA (typ) near -0.50 V on its own axis
|   POWER clamp passes 1 mA (typ) near -0.46 V on its own axis
[POWER_clamp]
|   voltage   I(typ)   I(min)   I(max)
-1.8V     107.1mA    82.39mA    134mA
-1.309V   51.22mA    36.03mA    66.85mA
-1.255V   45.3mA     31.42mA    59.51mA
-1.145V   33.99mA    23.05mA    45.2mA
-1.091V   28.82mA    19.51mA    38.41mA
-1.036V   24.21mA    16.51mA    32.11mA
-981.8mV  20.35mA    13.99mA    26.63mA
-818.2mV  11.74mA    7.854mA    15.24mA
-654.5mV  5.636mA    3.007mA    7.414mA
-490.9mV  1.465mA    582.8uA    1.573mA
-272.7mV  11.26uA    9.618uA    3.791uA
3.545V    0A         0A         0A
[GND_clamp]
|   voltage   I(typ)   I(min)   I(max)
-1.8V     -229.3mA   -132mA     -818.5mA
-1.745V   -215.7mA   -124mA     -769.6mA
-1.691V   -202.2mA   -116mA     -720.6mA
-1.364V   -121.2mA   -68.84mA   -424.9mA
-1.036V   -45.71mA   -27.15mA   -136.8mA
-981.8mV  -35.25mA   -21.76mA   -94.05mA
-927.3mV  -26.04mA   -16.99mA   -56.46mA
-872.7mV  -18.27mA   -12.8mA    -28.74mA
-818.2mV  -12.44mA   -9.251mA   -16.16mA
-654.5mV  -4.789mA   -3.281mA   -6.529mA
-381.8mV  -101.3uA   -119.5uA   -85.82uA
3.545V    0A         0A         0A
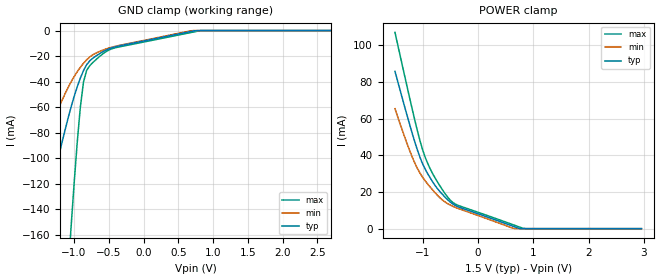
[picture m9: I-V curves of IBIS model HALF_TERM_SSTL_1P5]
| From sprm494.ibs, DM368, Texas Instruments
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|   Model Cell HALF_TERM_SSTL_1P5
|HALF_TERM_SSTL_1P5
[Model]   HALF_TERM_SSTL_1P5
Model_type   Input
Polarity   Non-Inverting
Vinl =  0.65
Vinh =  0.85
C_comp   3.047242p   2.257596p   4.009695p
[Model Spec]
Vinl   0.65   0.575   0.725
Vinh   0.85   0.775   0.925
[Temperature Range]   25   125   -40
[Voltage Range]   1.5   1.35   1.65
[POWER_clamp]
|   voltage   I(typ)   I(min)   I(max)
-1.5V     85.79mA    65.41mA    107mA
-1.318V   65.71mA    49.42mA    82.38mA
-1.182V   51.29mA    38.61mA    64.32mA
-1.091V   42.54mA    32.6mA     52.93mA
-1V       35.33mA    28mA       42.96mA
-909.1mV  29.98mA    24.34mA    35.6mA
-772.7mV  23.44mA    19.51mA    27.52mA
-590.9mV  17.05mA    14.45mA    18.92mA
-454.5mV  13.46mA    12.19mA    14.28mA
636.4mV   1.292mA    192.7uA    2.127mA
818.2mV   0A         0A         141.1uA
2.955V    0A         0A         0A
[GND_clamp]
|   voltage   I(typ)   I(min)   I(max)
-1.5V     -164.2mA   -97.77mA   -554.2mA
-1.455V   -153.3mA   -91.45mA   -513.5mA
-1.182V   -89.43mA   -55.71mA   -271.2mA
-1.045V   -60.37mA   -40.45mA   -156mA
-954.5mV  -44.04mA   -32.24mA   -87.69mA
-909.1mV  -37.15mA   -28.74mA   -59.76mA
-863.6mV  -31.25mA   -25.6mA    -40.11mA
-818.2mV  -26.67mA   -22.85mA   -31.06mA
-681.8mV  -19.78mA   -17.53mA   -22.6mA
-409.1mV  -12.75mA   -12.35mA   -13.5mA
818.2mV   0A         0A         -8.294uA
2.955V    0A         0A         0A
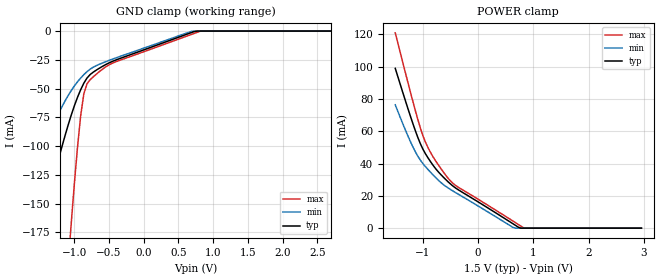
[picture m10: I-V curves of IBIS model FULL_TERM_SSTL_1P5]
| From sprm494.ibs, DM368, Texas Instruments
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|   Model Cell FULL_TERM_SSTL_1P5
|FULL_TERM_SSTL_1P5
[Model]   FULL_TERM_SSTL_1P5
Model_type   Input
Polarity   Non-Inverting
Vinl =  0.65
Vinh =  0.85
C_comp   3.047242p   2.257596p   4.009695p
[Model Spec]
Vinl   0.65   0.575   0.725
Vinh   0.85   0.775   0.925
[Temperature Range]   25   125   -40
[Voltage Range]   1.5   1.35   1.65
[POWER_clamp]
|   voltage   I(typ)   I(min)   I(max)
-1.5V     98.88mA    76.33mA    120.8mA
-1.182V   64.76mA    50.34mA    78.46mA
-1.045V   52.24mA    42.08mA    61.93mA
-954.5mV  46.08mA    38.11mA    53.28mA
-818.2mV  39.02mA    33.05mA    44.24mA
-681.8mV  33.4mA     28.46mA    37.24mA
-545.5mV  28.72mA    24.92mA    30.97mA
-409.1mV  24.86mA    22.02mA    26.44mA
636.4mV   2.581mA    339.3uA    4.25mA
727.3mV   598.1uA    0A         2.269mA
818.2mV   0A         0A         281.9uA
2.955V    0A         0A         0A
[GND_clamp]
|   voltage   I(typ)   I(min)   I(max)
-1.5V     -173.6mA   -106.5mA   -560.1mA
-1.091V   -82.02mA   -56.21mA   -204.3mA
-1.045V   -73.16mA   -51.74mA   -167.7mA
-954.5mV  -57.59mA   -44.08mA   -101mA
-909.1mV  -51mA      -40.82mA   -73.73mA
-863.6mV  -45.32mA   -37.88mA   -54.62mA
-818.2mV  -40.85mA   -35.27mA   -45.89mA
-681.8mV  -33.85mA   -29.97mA   -37.37mA
-409.1mV  -25.29mA   -23.46mA   -26.81mA
681.8mV   -1.39mA    -335.8uA   -3.005mA
818.2mV   0A         0A         -16.57uA
2.955V    0A         0A         0A
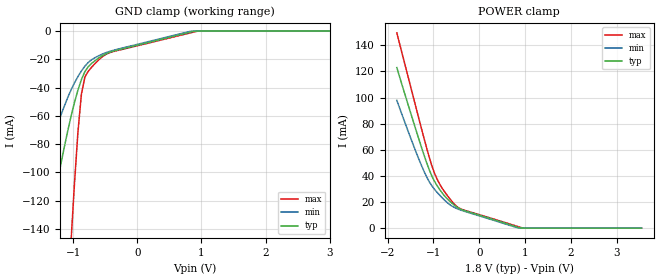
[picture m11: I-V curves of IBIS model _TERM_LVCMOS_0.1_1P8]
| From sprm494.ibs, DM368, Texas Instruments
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|   Model Cell _TERM_LVCMOS_0.1_1P8
|HALF_TERM_LVCMOS_0.1_1P8
[Model]   _TERM_LVCMOS_0.1_1P8
Model_type   Input
Polarity   Non-Inverting
Vinl =  0.63
Vinh =  1.17
C_comp   3.009089p   2.23501p   3.95018p
[Model Spec]
Vinl   0.63   0.595   0.665
Vinh   1.17   1.105   1.235
[Temperature Range]   25   125   -40
[Voltage Range]   1.8   1.7   1.9
[POWER_clamp]
|   voltage   I(typ)   I(min)   I(max)
-1.8V     122.9mA    97.85mA    149.5mA
-1.309V   67.07mA    52mA       82.56mA
-1.145V   49.82mA    39.05mA    60.97mA
-1.036V   40.01mA    32.49mA    47.91mA
-927.3mV  32.91mA    27.67mA    38.06mA
-818.2mV  27.38mA    23.58mA    31.06mA
-654.5mV  20.99mA    18.3mA     23.04mA
-490.9mV  16.21mA    15.02mA    16.65mA
-327.3mV  13.47mA    12.96mA    13.76mA
818.2mV   986.3uA    455.6uA    1.533mA
981.8mV   0A         0A         0A
3.545V    0A         0A         0A
[GND_clamp]
|   voltage   I(typ)   I(min)   I(max)
-1.8V     -238.9mA   -143.1mA   -823mA
-1.418V   -146.7mA   -89.2mA    -482.3mA
-1.364V   -133.7mA   -81.8mA    -433.5mA
-1.036V   -60.59mA   -41.78mA   -150mA
-981.8mV  -50.58mA   -36.68mA   -108.2mA
-927.3mV  -41.77mA   -32.18mA   -71.53mA
-872.7mV  -34.29mA   -28.21mA   -44.54mA
-818.2mV  -28.61mA   -24.8mA    -32.43mA
-654.5mV  -20.75mA   -18.66mA   -22.68mA
-436.4mV  -15.06mA   -14.43mA   -15.34mA
927.3mV   0A         0A         -167.4uA
3.545V    0A         0A         0A
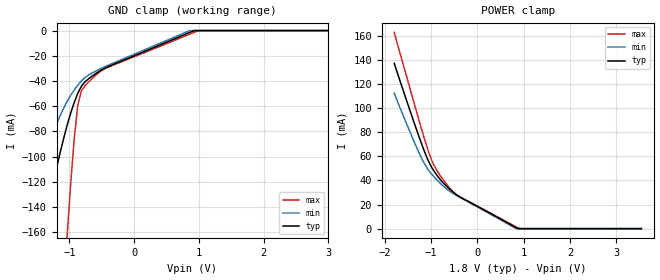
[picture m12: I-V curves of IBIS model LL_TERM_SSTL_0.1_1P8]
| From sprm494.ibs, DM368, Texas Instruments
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|   Model Cell LL_TERM_SSTL_0.1_1P8
|FULL_TERM_SSTL_0.1_1P8
[Model]   LL_TERM_SSTL_0.1_1P8
Model_type   Input
Polarity   Non-Inverting
Vinl =  0.8
Vinh =  1
C_comp   3.009089p   2.23501p   3.95018p
[Model Spec]
Vinl   0.8   0.75   0.85
Vinh   1   0.95   1.05
[Temperature Range]   25   125   -40
[Voltage Range]   1.8   1.7   1.9
[POWER_clamp]
|   voltage   I(typ)   I(min)   I(max)
-1.8V     137.1mA    112.3mA    162.7mA
-1.309V   81.24mA    66.89mA    95.93mA
-1.145V   63.98mA    53.96mA    74.43mA
-1.036V   54.18mA    47.37mA    61.46mA
-927.3mV  47.05mA    42.47mA    51.68mA
-818.2mV  41.41mA    38.21mA    44.67mA
-600mV    32.76mA    30.97mA    33.73mA
-436.4mV  27.7mA     27.16mA    27.56mA
818.2mV   1.165mA    454.4uA    1.822mA
872.7mV   0A         0A         683.8uA
927.3mV   0A         0A         0A
3.545V    0A         0A         0A
[GND_clamp]
|   voltage   I(typ)   I(min)   I(max)
-1.8V     -248.2mA   -154mA     -827.4mA
-1.418V   -158.5mA   -101.6mA   -490.2mA
-1.2V     -108.8mA   -73.97mA   -298.7mA
-1.036V   -75.1mA    -56.16mA   -162.8mA
-927.3mV  -57.07mA   -47.1mA    -86.02mA
-872.7mV  -49.87mA   -43.34mA   -59.72mA
-818.2mV  -44.34mA   -40.06mA   -48.08mA
-763.6mV  -40.8mA    -37.39mA   -43.97mA
-490.9mV  -30.82mA   -29.56mA   -31.32mA
818.2mV   -2.352mA   -925.3uA   -3.69mA
927.3mV   -5.951uA   0A         -1.407mA
3.545V    0A         0A         0A
